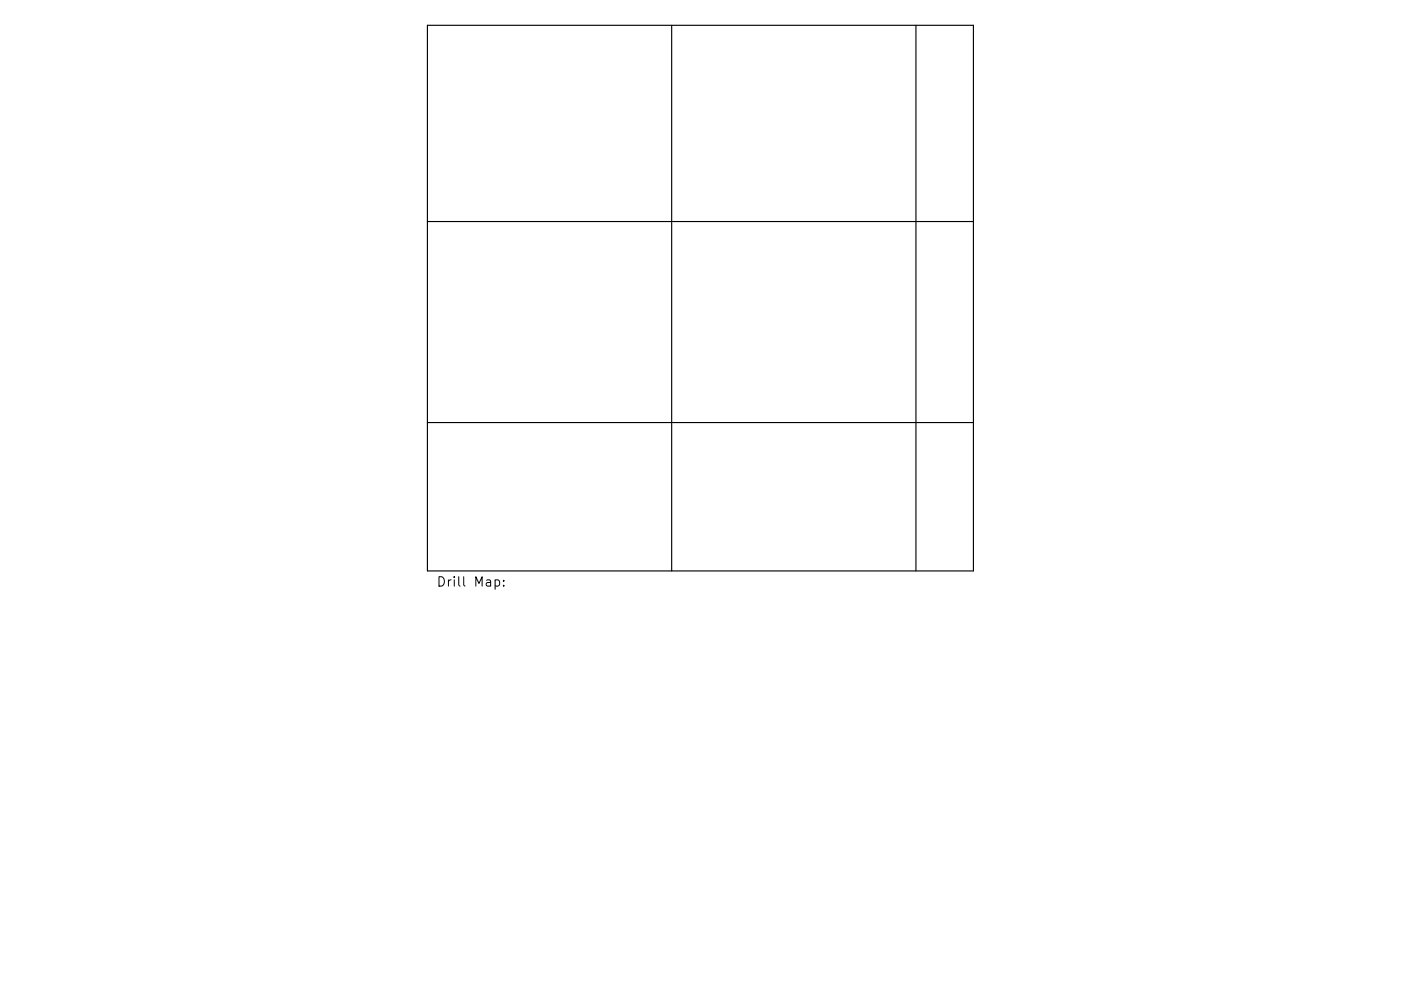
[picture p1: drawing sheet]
<svg xmlns="http://www.w3.org/2000/svg" width="297mm" height="210mm" viewBox="0 0 297 210" stroke-linecap="round" stroke-linejoin="round" font-family="sans-serif">
<defs><g id="words">
<g font-size="2.8">
<text x="92.5" y="125.1">Drill</text>
<text x="100.5" y="125.1">Map:</text>
</g>
</g></defs>
<path d="M90.6 5.4h115.8v115.7h-115.8zM142.4 5.4v115.7M194.2 5.4v115.7M90.6 47h115.8M90.6 89.7h115.8" fill="none" stroke="#000" stroke-width=".24"/>
<path d="M98.3 122.4v1.7l.3 .3" fill="none" stroke="#000" stroke-width=".21"/>
<use href="#words"/>
</svg>
